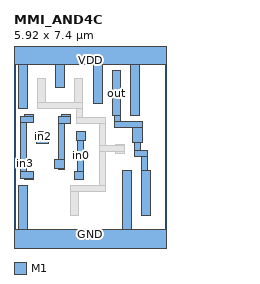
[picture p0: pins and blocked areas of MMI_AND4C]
MACRO MMI_AND4C
	CLASS CORE ;
	FOREIGN MMI_AND4C 0 0 ;
	SIZE 5.92 BY 7.4 ;
	SYMMETRY X Y ;
	SITE CORE1 ;
	PIN out
		DIRECTION output ;
		USE SIGNAL ;
		PORT
			LAYER M1 ;
			RECT 3.82 4.91 4.16 6.67 ;
			LAYER M1 ;
			RECT 3.93 4.675 4.16 4.91 ;
			LAYER M1 ;
			RECT 3.93 4.445 5 4.675 ;
			LAYER M1 ;
			RECT 4.61 3.885 5 4.445 ;
			LAYER M1 ;
			RECT 4.695 3.56 4.925 3.885 ;
			LAYER M1 ;
			RECT 4.695 3.33 5.19 3.56 ;
			LAYER M1 ;
			RECT 4.96 2.79 5.19 3.33 ;
			LAYER M1 ;
			RECT 4.96 1.03 5.3 2.79 ;
		END
		AntennaDiffArea 1.8768 ;
	END out
	PIN in1
		DIRECTION input ;
		USE SIGNAL ;
		PORT
			LAYER M1 ;
			RECT 1.86 4.87 2.2 4.965 ;
			LAYER M1 ;
			RECT 1.735 4.625 2.2 4.87 ;
			LAYER M1 ;
			RECT 1.735 3.195 1.965 4.625 ;
			LAYER M1 ;
			RECT 1.585 2.855 1.965 3.195 ;
			LAYER M1 ;
			RECT 1.735 2.805 1.965 2.855 ;
		END
		AntennaGateArea 0.6696 ;
	END in1
	PIN GND
		DIRECTION inout ;
		USE GROUND ;
		PORT
			LAYER M1 ;
			RECT 0.18 0.5 0.52 2.19 ;
			LAYER M1 ;
			RECT 4.24 0.5 4.58 2.79 ;
			LAYER M1 ;
			RECT 0 -0.5 5.92 0.5 ;
		END
	END GND
	PIN in2
		DIRECTION input ;
		USE SIGNAL ;
		PORT
			LAYER M1 ;
			RECT 0.885 3.955 1.39 4.295 ;
			LAYER M1 ;
			RECT 0.885 3.845 1.335 3.955 ;
		END
		AntennaGateArea 0.6696 ;
	END in2
	PIN VDD
		DIRECTION inout ;
		USE POWER ;
		PORT
			LAYER M1 ;
			RECT 0 6.9 5.92 7.9 ;
			LAYER M1 ;
			RECT 0.18 5.205 0.52 6.9 ;
			LAYER M1 ;
			RECT 1.62 6.025 1.96 6.9 ;
			LAYER M1 ;
			RECT 3.1 5.39 3.44 6.9 ;
			LAYER M1 ;
			RECT 4.54 4.91 4.88 6.9 ;
		END
	END VDD
	PIN in3
		DIRECTION input ;
		USE SIGNAL ;
		PORT
			LAYER M1 ;
			RECT 0.42 4.885 0.76 4.975 ;
			LAYER M1 ;
			RECT 0.255 4.635 0.76 4.885 ;
			LAYER M1 ;
			RECT 0.255 2.76 0.485 4.635 ;
			LAYER M1 ;
			RECT 0.255 2.475 0.76 2.76 ;
			LAYER M1 ;
			RECT 0.42 2.42 0.76 2.475 ;
		END
		AntennaGateArea 0.6696 ;
	END in3
	PIN in0
		DIRECTION input ;
		USE SIGNAL ;
		PORT
			LAYER M1 ;
			RECT 2.435 3.955 2.775 4.295 ;
			LAYER M1 ;
			RECT 2.475 2.765 2.705 3.955 ;
			LAYER M1 ;
			RECT 2.365 2.425 2.705 2.765 ;
		END
		AntennaGateArea 0.6696 ;
	END in0
	OBS
		LAYER M1 ;
		RECT 0.9 5.435 1.24 6.365 ;
		LAYER M1 ;
		RECT 2.34 5.435 2.68 6.365 ;
		LAYER M1 ;
		RECT 0.9 5.205 2.68 5.435 ;
		LAYER M1 ;
		RECT 2.45 4.845 2.68 5.205 ;
		LAYER M1 ;
		RECT 2.45 4.615 3.57 4.845 ;
		LAYER M1 ;
		RECT 3.34 3.745 3.57 4.615 ;
		LAYER M1 ;
		RECT 3.97 3.745 4.31 3.8 ;
		LAYER M1 ;
		RECT 3.34 3.515 4.31 3.745 ;
		LAYER M1 ;
		RECT 3.34 2.19 3.57 3.515 ;
		LAYER M1 ;
		RECT 3.97 3.46 4.31 3.515 ;
		LAYER M1 ;
		RECT 2.19 1.96 3.57 2.19 ;
		LAYER M1 ;
		RECT 2.19 1.03 2.53 1.96 ;
	END
END MMI_AND4C
